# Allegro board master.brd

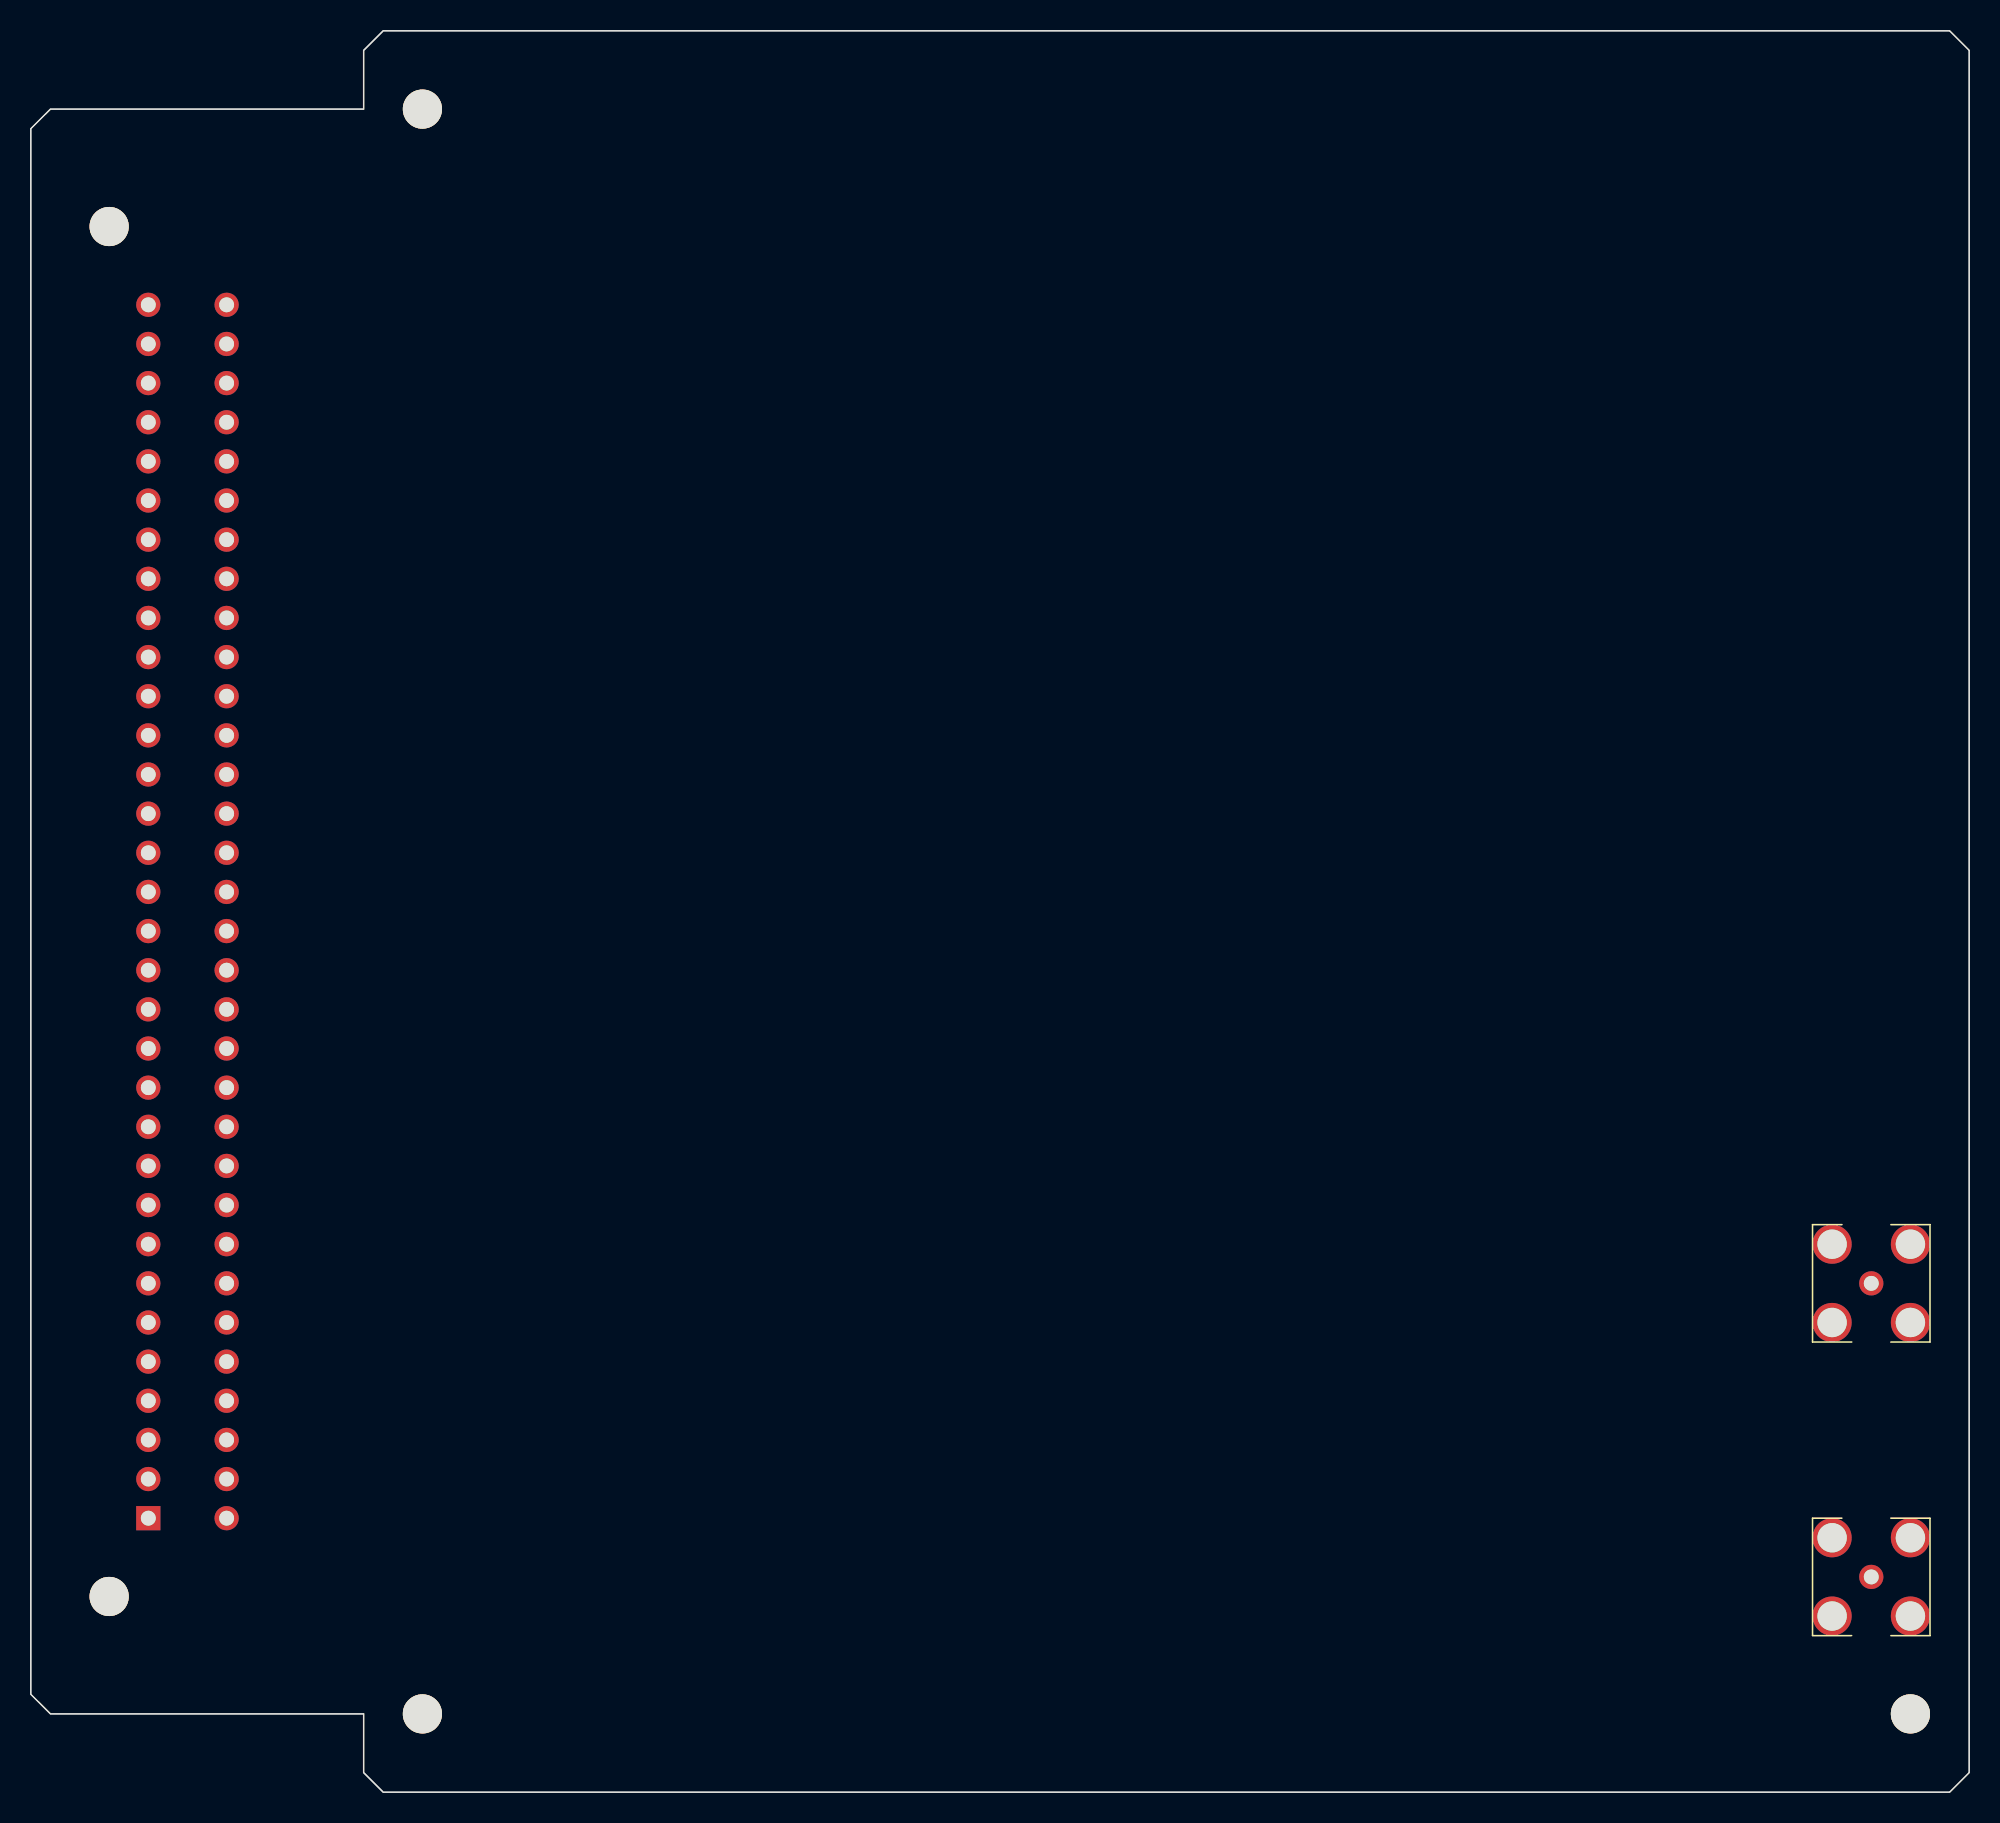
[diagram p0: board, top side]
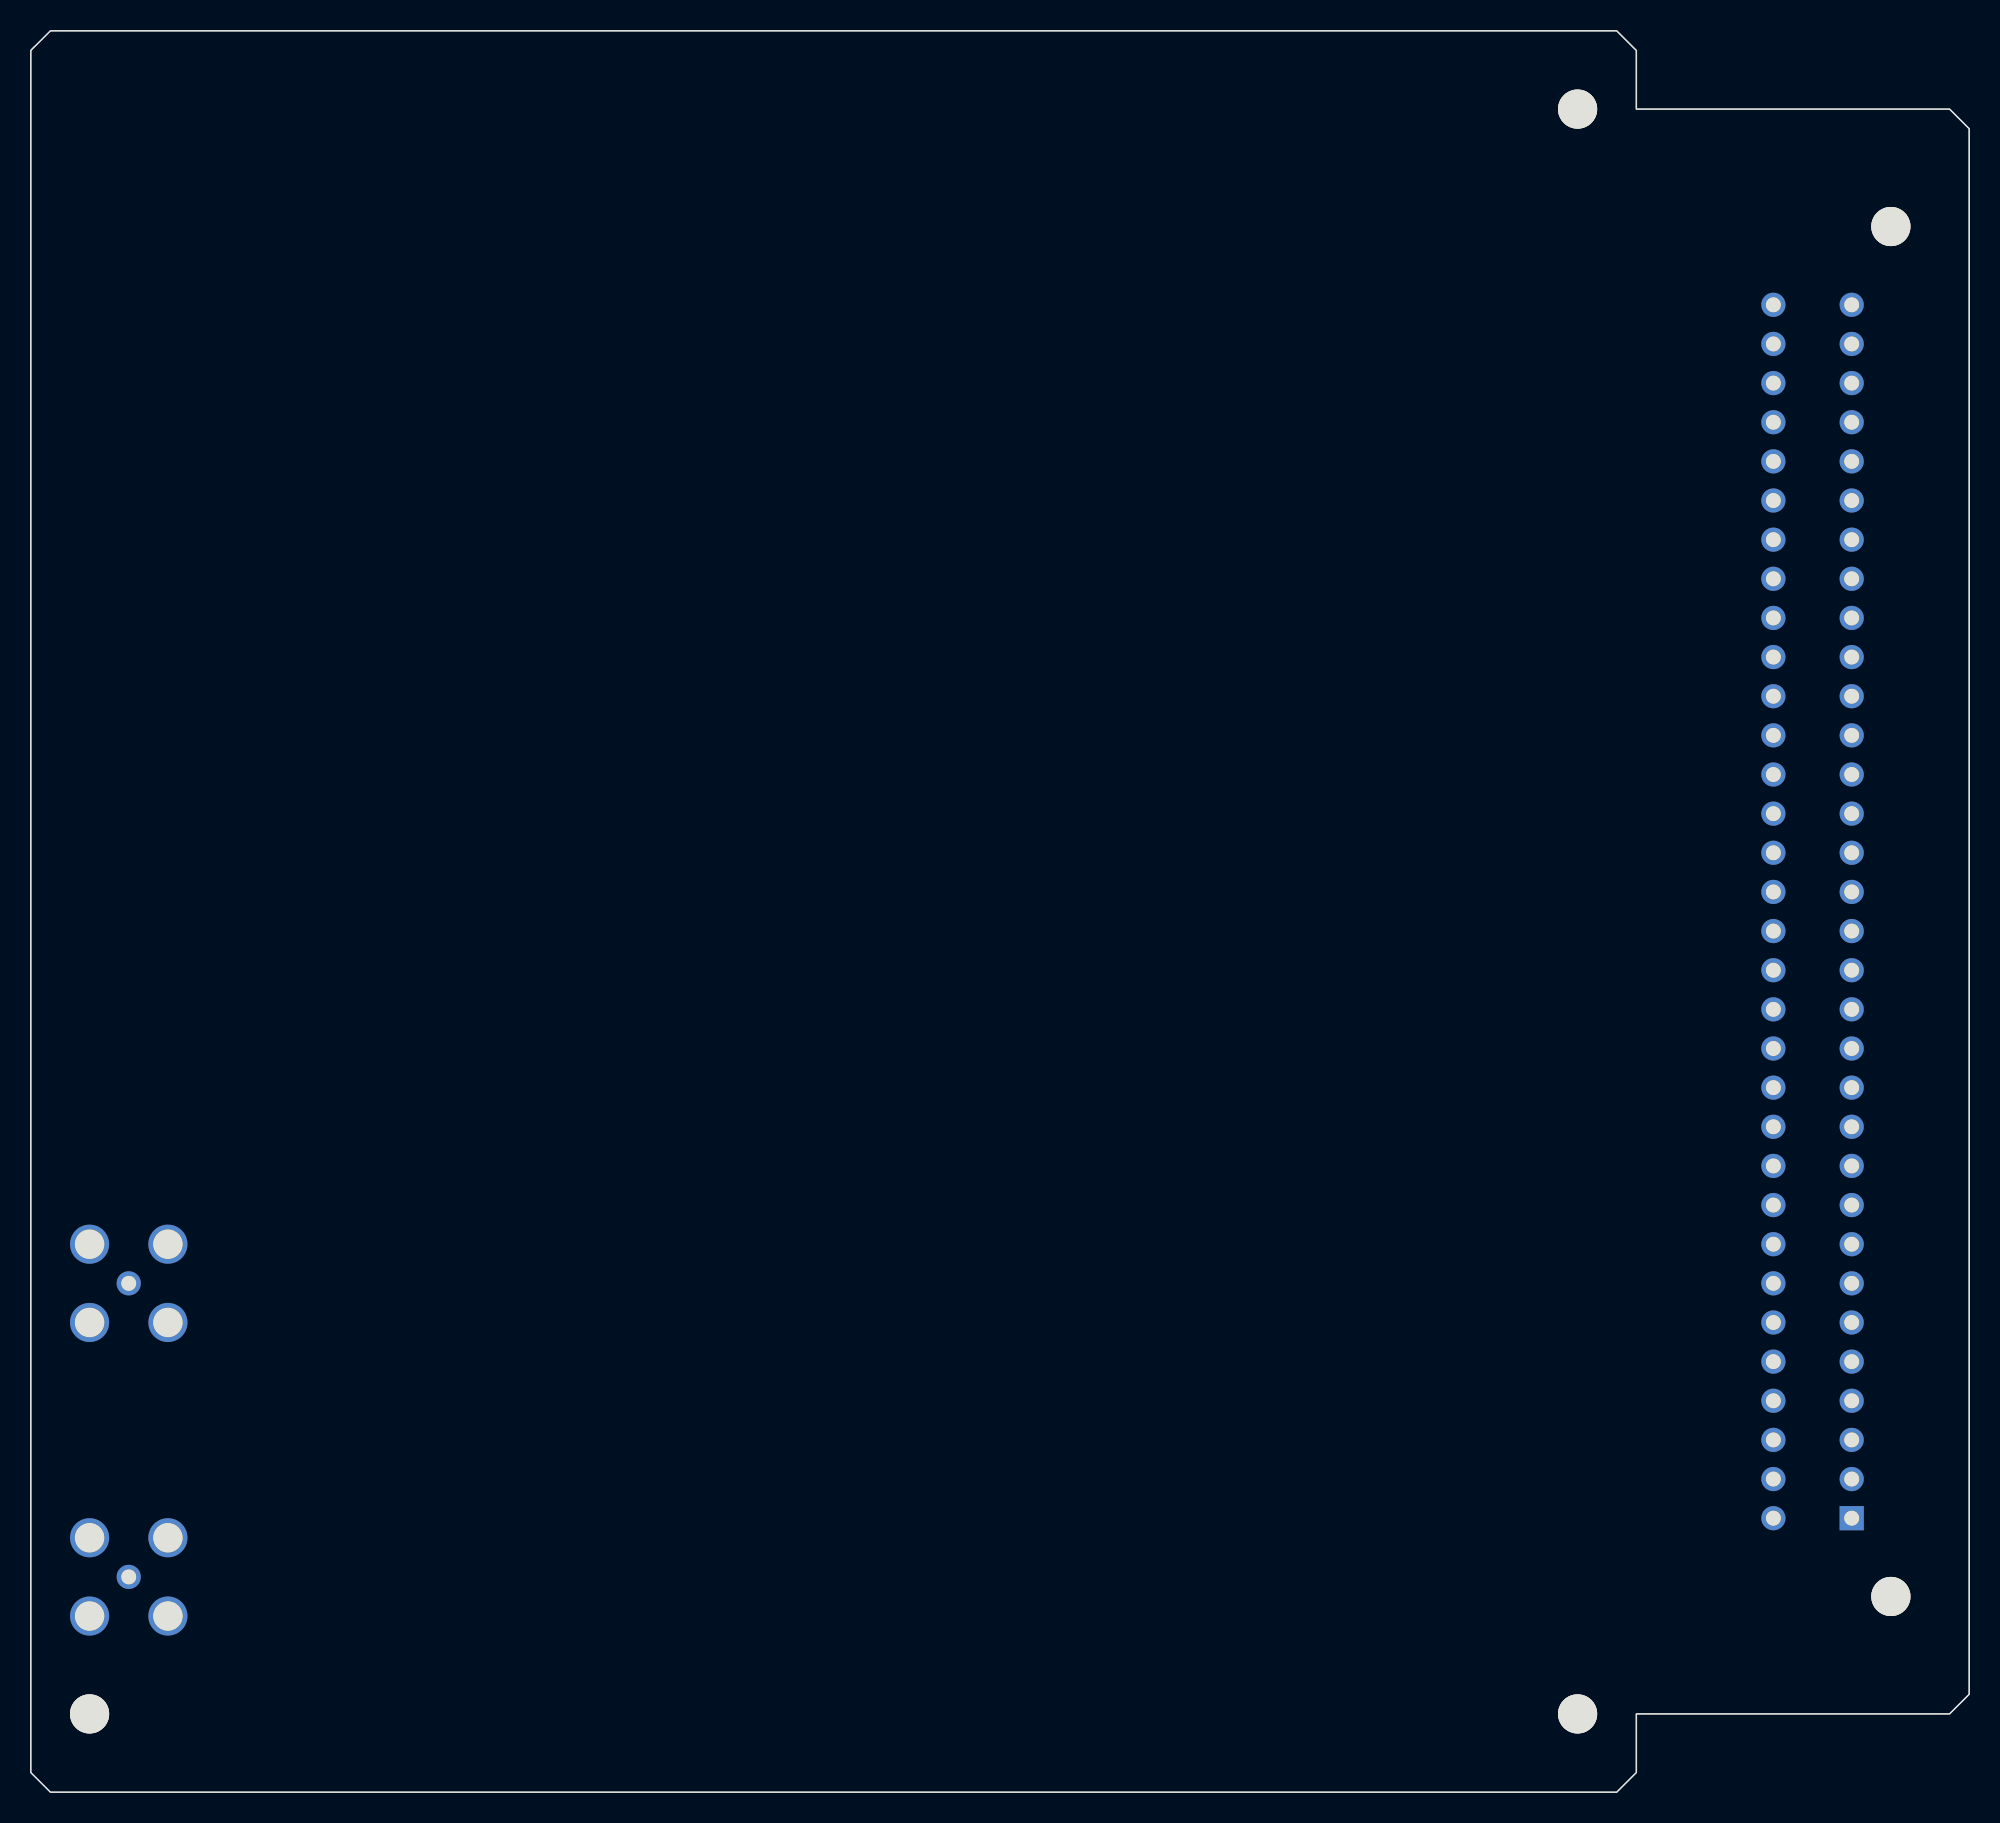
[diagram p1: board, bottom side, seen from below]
Outline 125.73 x 114.3 mm; copper layers: TOP, GND, VCC, BOTTOM. Coordinates in mm from the lower left corner of the outline.

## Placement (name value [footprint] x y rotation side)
J*  -  [unnamed]  119.38 13.97 0 top
J*#2  -  [unnamed#3]  7.62 17.78 0 top
J*#3  -  [unnamed]  119.38 33.02 0 top
NOREF  -  [#2]  -30.48 -55.88 0 top
NOREF#2  -  [#2]  259.08 129.54 0 top
NOREF#3  -  [unnamed#4]  25.4 5.08 0 top

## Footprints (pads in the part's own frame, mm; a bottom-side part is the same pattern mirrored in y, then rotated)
unnamed
  round 1.575 hole 0.965: 1(0,0)
  round 2.54 hole 1.905: 2(-2.54,2.54) 3(-2.54,-2.54) 4(2.54,2.54) 5(2.54,-2.54)
unnamed#3
  round 2.54 hole 2.794 unplated: (-2.54,83.82) (-2.54,-5.08)
  rect 1.575x1.575 hole 0.965: 1(0,0)
  round 1.575 hole 0.965: 2(0,2.54) 3(0,5.08) 4(0,7.62) 5(0,10.16) 6(0,12.7) 7(0,15.24) 8(0,17.78) 9(0,20.32) 10(0,22.86) 11(0,25.4) 12(0,27.94) 13(0,30.48) 14(0,33.02) 15(0,35.56) 16(0,38.1) 17(0,40.64) 18(0,43.18) 19(0,45.72) 20(0,48.26) 21(0,50.8) 22(0,53.34) 23(0,55.88) 24(0,58.42) 25(0,60.96) 26(0,63.5) 27(0,66.04) 28(0,68.58) 29(0,71.12) 30(0,73.66) 31(0,76.2) 32(0,78.74) 33(5.08,0) 34(5.08,2.54) 35(5.08,5.08) 36(5.08,7.62) 37(5.08,10.16) 38(5.08,12.7) 39(5.08,15.24) 40(5.08,17.78) 41(5.08,20.32) 42(5.08,22.86) 43(5.08,25.4) 44(5.08,27.94) 45(5.08,30.48) 46(5.08,33.02) 47(5.08,35.56) 48(5.08,38.1) 49(5.08,40.64) 50(5.08,43.18) 51(5.08,45.72) 52(5.08,48.26) 53(5.08,50.8) 54(5.08,53.34) 55(5.08,55.88) 56(5.08,58.42) 57(5.08,60.96) 58(5.08,63.5) 59(5.08,66.04) 60(5.08,68.58) 61(5.08,71.12) 62(5.08,73.66) 63(5.08,76.2) 64(5.08,78.74)
unnamed#4
  round 2.54 hole 2.794 unplated: (0,104.14) (0,0) (96.52,0)

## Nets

Pads without a net: J* 1 2 3 4 5; J*#2 1 2 3 4 5 6 7 8 9 10 11 12 13 14 15 16 17 18 19 20 21 22 23 24 25 26 27 28 29 30 31 32 33 34 35 36 37 38 39 40 41 42 43 44 45 46 47 48 49 50 51 52 53 54 55 56 57 58 59 60 61 62 63 64; J*#3 1 2 3 4 5
